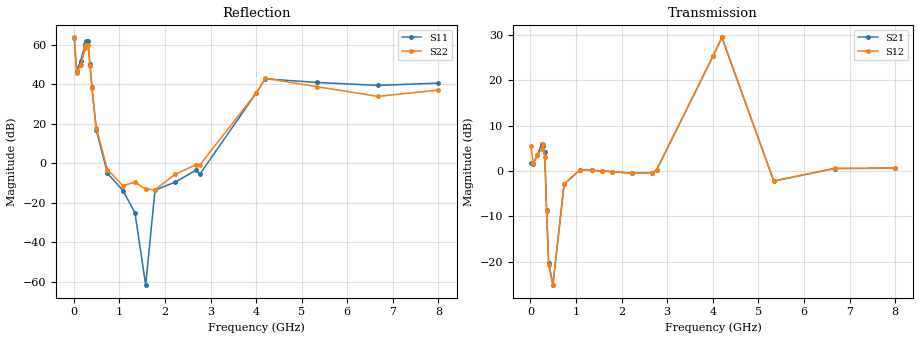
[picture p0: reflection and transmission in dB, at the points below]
!Agilent Technologies,N5230A,US43500312,A.07.50.67
!Agilent N5230A: A.07.50.67
!Date: Tuesday, June 09, 2015 15:39:32
!Correction: S11(Full 2 Port(1,2))
!S21(Full 2 Port(1,2))
!S12(Full 2 Port(1,2))
!S22(Full 2 Port(1,2))
!S2P File: Measurements: S11, S21, S12, S22:
# Hz S  MA  R 50
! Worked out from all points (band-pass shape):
!   1601 points, 10 MHz to 8 GHz, reference 50 ohm
!   highest |S21| = 29.45 dB at 4.2 GHz (marker M1); lowest = -25.1 dB at 494.4 MHz (marker M2)
!   |S21| within 3 dB of the highest: 4.042 GHz to 4.337 GHz (295.8 MHz wide, 7.06 % of centre)
!   lowest |S11| = -61.6 dB at 1.578 GHz (marker M3), VSWR 1.00, Z = 50 + j0.0769 ohm
!   |S11| at or under -10 dB: 922.9 MHz to 2.216 GHz (1.293 GHz wide, 82.4 % of centre); 2.843 GHz to 3.003 GHz (159.4 MHz wide, 5.45 % of centre)
!   |S22| runs from -14.4 to 63.6 dB; largest |S21 - S12| = 0.71
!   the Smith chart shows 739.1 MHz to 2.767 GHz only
!   S11 on the Smith chart (normalised r, x): 739.1 MHz: 0.31, -0.30; 1.079 GHz: 1.27, +0.39; 1.783 GHz: 0.96, +0.42; 2.227 GHz: 1.21, -0.75; 2.767 GHz: 0.82, -1.12
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1e7  1490 171.1  1.221 9.6  1.871 19.9  1520 -19.4
6.493125e7  221.2 337.9  1.203 5.0  1.219 -1.2  196.7 97.9
1.548188e8  392.9 400.0  1.507 3.3  1.504 2.8  301 121.9
2.497e8  1059 408.3  1.984 8.0  1.741 6.5  811.2 121.7
2.796625e8  1268 421.2  1.891 21.8  1.997 23.4  993.3 135.6
3.146188e8  1215 448.0  1.605 59.5  1.43 62.2  987.2 165.1
3.545688e8  330.2 473.4  0.3685 91.1  0.3631 83.4  285.1 197.2
3.995125e8  83.45 477.7  0.0974 81.0  0.09244 83.3  78.38 212.5
4.943938e8  6.819 491.6  0.05569 87.9  0.05503 86.9  7.863 264.9
7.390875e8  0.5612 575.8  0.7163 167.0  0.7136 167.1  0.6894 445.9
1.078662e9  0.2049 765.3  1.019 125.1  1.017 125.0  0.271 659.5
1.343331e9  0.05607 727.5  1.019 130.1  1.02 130.1  0.335 771.2
1.578038e9  0.0008344 787.1  0.9989 130.9  0.9997 131.0  0.2212 870.4
1.782781e9  0.2104 803.7  0.9824 128.4  0.9817 128.4  0.2149 978.1
2.227225e9  0.3351 664.3  0.9457 121.1  0.947 121.1  0.53 1129.4
2.676662e9  0.6673 650.6  0.957 135.4  0.9591 135.4  0.9142 1227.9
2.76655e9  0.5313 652.3  1.023 137.3  1.024 137.4  0.9071 1247.2
4.005e9  60.5 730.5  18.44 169.0  18.51 169.2  60.22 1532.4
4.199756e9  136.2 678.5  29.69 86.8  29.73 87.0  140.8 1486.7
5.338331e9  110.4 638.4  0.7718 19.9  0.7772 20.2  86.18 1415.0
6.671662e9  92.97 662.3  1.064 19.6  1.068 20.1  49.06 1356.7
8e9  106.4 680.1  1.071 12.7  1.073 13.6  70.92 1317.9
